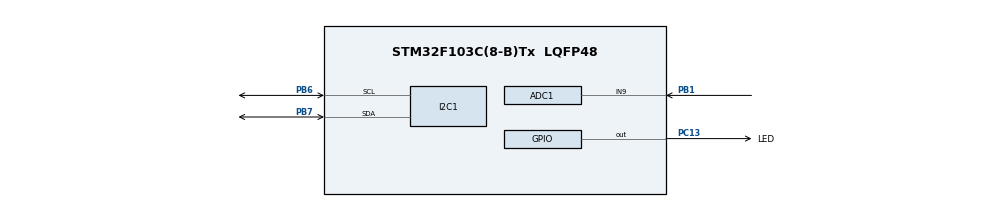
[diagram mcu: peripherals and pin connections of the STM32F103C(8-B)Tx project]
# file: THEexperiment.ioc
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ADC1.Channel-1\#ChannelRegularConversion=ADC_CHANNEL_9
ADC1.ContinuousConvMode=ENABLE
ADC1.NbrOfConversionFlag=1
ADC1.Rank-1\#ChannelRegularConversion=1
ADC1.SamplingTime-1\#ChannelRegularConversion=ADC_SAMPLETIME_1CYCLE_5
ADC1.master=1
I2C1.OwnAddress=0x68
Mcu.Family=STM32F1
Mcu.Name=STM32F103C(8-B)Tx
Mcu.Package=LQFP48
NVIC.ADC1_2_IRQn=true\:0\:0\:false\:false\:true\:true\:true\:true
NVIC.I2C1_ER_IRQn=true\:0\:0\:false\:false\:true\:true\:true\:true
NVIC.I2C1_EV_IRQn=true\:0\:0\:false\:false\:true\:true\:true\:true
NVIC.PriorityGroup=NVIC_PRIORITYGROUP_4
PA13.Mode=Serial_Wire
PA13.Signal=SYS_JTMS-SWDIO
PA14.Mode=Serial_Wire
PA14.Signal=SYS_JTCK-SWCLK
PB1.Signal=ADCx_IN9
PB6.Mode=I2C
PB6.Signal=I2C1_SCL
PB7.Mode=I2C
PB7.Signal=I2C1_SDA
PC13-TAMPER-RTC.GPIO_Label=LED
PC13-TAMPER-RTC.PinState=GPIO_PIN_RESET
PC13-TAMPER-RTC.Signal=GPIO_Output
PD0-OSC_IN.Mode=HSE-External-Oscillator
PD0-OSC_IN.Signal=RCC_OSC_IN
PD1-OSC_OUT.Mode=HSE-External-Oscillator
PD1-OSC_OUT.Signal=RCC_OSC_OUT
ProjectManager.HeapSize=0x200
ProjectManager.StackSize=0x400
ProjectManager.TargetToolchain=STM32CubeIDE
RCC.ADCPresc=RCC_ADCPCLK2_DIV6
RCC.AHBFreq_Value=64000000
RCC.APB1CLKDivider=RCC_HCLK_DIV2
RCC.APB1Freq_Value=32000000
RCC.APB1TimFreq_Value=64000000
RCC.APB2Freq_Value=64000000
RCC.APB2TimFreq_Value=64000000
RCC.HCLKFreq_Value=64000000
RCC.PLLMUL=RCC_PLL_MUL16
RCC.SYSCLKFreq_VALUE=64000000
RCC.SYSCLKSource=RCC_SYSCLKSOURCE_PLLCLK
RCC.USBFreq_Value=64000000
SH.ADCx_IN9.0=ADC1_IN9,IN9
TIM1.AutoReloadPreload=TIM_AUTORELOAD_PRELOAD_ENABLE
TIM1.Period=1536
TIM1.Prescaler=0
TIM1.RepetitionCounter=0
VP_TIM1_VS_ClockSourceINT.Mode=Internal
board=custom

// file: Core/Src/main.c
/* USER CODE BEGIN Header */
/**
  ******************************************************************************
  * @file           : main.c
  * @brief          : Main program body
  ******************************************************************************
  * @attention
  *
  * Copyright (c) 2024 STMicroelectronics.
  * All rights reserved.
  *
  * This software is licensed under terms that can be found in the LICENSE file
  * in the root directory of this software component.
  * If no LICENSE file comes with this software, it is provided AS-IS.
  *
  ******************************************************************************
  */
/* USER CODE END Header */
#include "main.h"

/* USER CODE BEGIN Includes */
#include "RequestQueue.h"
#include "i2c_queue.h"
#include "timer.h"
/* USER CODE END Includes */

ADC_HandleTypeDef hadc1;

I2C_HandleTypeDef hi2c1;

TIM_HandleTypeDef htim1;

void SystemClock_Config(void);
static void MX_GPIO_Init(void);
static void MX_ADC1_Init(void);
static void MX_I2C1_Init(void);
static void MX_TIM1_Init(void);

int main(void)
{

  /* MCU Configuration--------------------------------------------------------*/

  /* Reset of all peripherals, Initializes the Flash interface and the Systick. */
  HAL_Init();

  /* Configure the system clock */
  SystemClock_Config();

  /* Initialize all configured peripherals */
  MX_GPIO_Init();
  MX_ADC1_Init();
  MX_I2C1_Init();
  MX_TIM1_Init();
  /* USER CODE BEGIN 2 */
  HAL_GPIO_WritePin(GPIOB, GPIO_PIN_13, GPIO_PIN_SET);
   if(HAL_I2C_EnableListen_IT(&hi2c1) != HAL_OK){
  	  Error_Handler();
   }
   HAL_TIM_Base_Start(&htim1);
   HAL_ADC_Start(&hadc1);

   uint8_t data[] = {0xFF, 0x01, 0x02, 0x03, 0x04, 0x05, 0x06, 0x07, 0x08, 0x09, 0x0A, 0x0B, 0x0C, 0x0D, 0x0E};
   queue_push(data, false, false);

  /* USER CODE END 2 */

  /* Infinite loop */
  while (1)
  {

  }
}

void SystemClock_Config(void)
{
  RCC_OscInitTypeDef RCC_OscInitStruct = {0};
  RCC_ClkInitTypeDef RCC_ClkInitStruct = {0};
  RCC_PeriphCLKInitTypeDef PeriphClkInit = {0};

  /** Initializes the RCC Oscillators according to the specified parameters
  * in the RCC_OscInitTypeDef structure.
  */
  RCC_OscInitStruct.OscillatorType = RCC_OSCILLATORTYPE_HSE;
  RCC_OscInitStruct.HSEState = RCC_HSE_ON;
  RCC_OscInitStruct.HSEPredivValue = RCC_HSE_PREDIV_DIV1;
  RCC_OscInitStruct.HSIState = RCC_HSI_ON;
  RCC_OscInitStruct.PLL.PLLState = RCC_PLL_ON;
  RCC_OscInitStruct.PLL.PLLSource = RCC_PLLSOURCE_HSE;
  RCC_OscInitStruct.PLL.PLLMUL = RCC_PLL_MUL9;
  if (HAL_RCC_OscConfig(&RCC_OscInitStruct) != HAL_OK)
  {
    Error_Handler();
  }

  /** Initializes the CPU, AHB and APB buses clocks
  */
  RCC_ClkInitStruct.ClockType = RCC_CLOCKTYPE_HCLK|RCC_CLOCKTYPE_SYSCLK
                              |RCC_CLOCKTYPE_PCLK1|RCC_CLOCKTYPE_PCLK2;
  RCC_ClkInitStruct.SYSCLKSource = RCC_SYSCLKSOURCE_PLLCLK;
  RCC_ClkInitStruct.AHBCLKDivider = RCC_SYSCLK_DIV1;
  RCC_ClkInitStruct.APB1CLKDivider = RCC_HCLK_DIV2;
  RCC_ClkInitStruct.APB2CLKDivider = RCC_HCLK_DIV1;

  if (HAL_RCC_ClockConfig(&RCC_ClkInitStruct, FLASH_LATENCY_2) != HAL_OK)
  {
    Error_Handler();
  }
  PeriphClkInit.PeriphClockSelection = RCC_PERIPHCLK_ADC;
  PeriphClkInit.AdcClockSelection = RCC_ADCPCLK2_DIV6;
  if (HAL_RCCEx_PeriphCLKConfig(&PeriphClkInit) != HAL_OK)
  {
    Error_Handler();
  }

  /** Enables the Clock Security System
  */
  HAL_RCC_EnableCSS();
}

static void MX_ADC1_Init(void)
{

  ADC_ChannelConfTypeDef sConfig = {0};

  /** Common config
  */
  hadc1.Instance = ADC1;
  hadc1.Init.ScanConvMode = ADC_SCAN_DISABLE;
  hadc1.Init.ContinuousConvMode = ENABLE;
  hadc1.Init.DiscontinuousConvMode = DISABLE;
  hadc1.Init.ExternalTrigConv = ADC_SOFTWARE_START;
  hadc1.Init.DataAlign = ADC_DATAALIGN_RIGHT;
  hadc1.Init.NbrOfConversion = 1;
  if (HAL_ADC_Init(&hadc1) != HAL_OK)
  {
    Error_Handler();
  }

  /** Configure Regular Channel
  */
  sConfig.Channel = ADC_CHANNEL_9;
  sConfig.Rank = ADC_REGULAR_RANK_1;
  sConfig.SamplingTime = ADC_SAMPLETIME_1CYCLE_5;
  if (HAL_ADC_ConfigChannel(&hadc1, &sConfig) != HAL_OK)
  {
    Error_Handler();
  }

}

static void MX_I2C1_Init(void)
{

  hi2c1.Instance = I2C1;
  hi2c1.Init.ClockSpeed = 100000;
  hi2c1.Init.DutyCycle = I2C_DUTYCYCLE_2;
  hi2c1.Init.OwnAddress1 = 208;
  hi2c1.Init.AddressingMode = I2C_ADDRESSINGMODE_7BIT;
  hi2c1.Init.DualAddressMode = I2C_DUALADDRESS_DISABLE;
  hi2c1.Init.OwnAddress2 = 0;
  hi2c1.Init.GeneralCallMode = I2C_GENERALCALL_DISABLE;
  hi2c1.Init.NoStretchMode = I2C_NOSTRETCH_DISABLE;
  if (HAL_I2C_Init(&hi2c1) != HAL_OK)
  {
    Error_Handler();
  }

}

static void MX_TIM1_Init(void)
{

  TIM_ClockConfigTypeDef sClockSourceConfig = {0};
  TIM_MasterConfigTypeDef sMasterConfig = {0};

  htim1.Instance = TIM1;
  htim1.Init.Prescaler = 72;
  htim1.Init.CounterMode = TIM_COUNTERMODE_UP;
  htim1.Init.Period = 65535;
  htim1.Init.ClockDivision = TIM_CLOCKDIVISION_DIV1;
  htim1.Init.RepetitionCounter = 0;
  htim1.Init.AutoReloadPreload = TIM_AUTORELOAD_PRELOAD_DISABLE;
  if (HAL_TIM_Base_Init(&htim1) != HAL_OK)
  {
    Error_Handler();
  }
  sClockSourceConfig.ClockSource = TIM_CLOCKSOURCE_INTERNAL;
  if (HAL_TIM_ConfigClockSource(&htim1, &sClockSourceConfig) != HAL_OK)
  {
    Error_Handler();
  }
  sMasterConfig.MasterOutputTrigger = TIM_TRGO_RESET;
  sMasterConfig.MasterSlaveMode = TIM_MASTERSLAVEMODE_DISABLE;
  if (HAL_TIMEx_MasterConfigSynchronization(&htim1, &sMasterConfig) != HAL_OK)
  {
    Error_Handler();
  }

}

static void MX_GPIO_Init(void)
{
  GPIO_InitTypeDef GPIO_InitStruct = {0};

  /* GPIO Ports Clock Enable */
  __HAL_RCC_GPIOC_CLK_ENABLE();
  __HAL_RCC_GPIOD_CLK_ENABLE();
  __HAL_RCC_GPIOB_CLK_ENABLE();
  __HAL_RCC_GPIOA_CLK_ENABLE();

  /*Configure GPIO pin Output Level */
  HAL_GPIO_WritePin(LED_GPIO_Port, LED_Pin, GPIO_PIN_RESET);

  /*Configure GPIO pin : LED_Pin */
  GPIO_InitStruct.Pin = LED_Pin;
  GPIO_InitStruct.Mode = GPIO_MODE_OUTPUT_PP;
  GPIO_InitStruct.Pull = GPIO_NOPULL;
  GPIO_InitStruct.Speed = GPIO_SPEED_FREQ_LOW;
  HAL_GPIO_Init(LED_GPIO_Port, &GPIO_InitStruct);

}

/* USER CODE BEGIN 4 */
void delay (int x)
{
  volatile int i,j;
  for (i=0 ; i < x ; i++)
  {
     j++;
  }
  return;
}
/* USER CODE END 4 */

void Error_Handler(void)
{
  __disable_irq();
  while (1)
  {
  }
}
